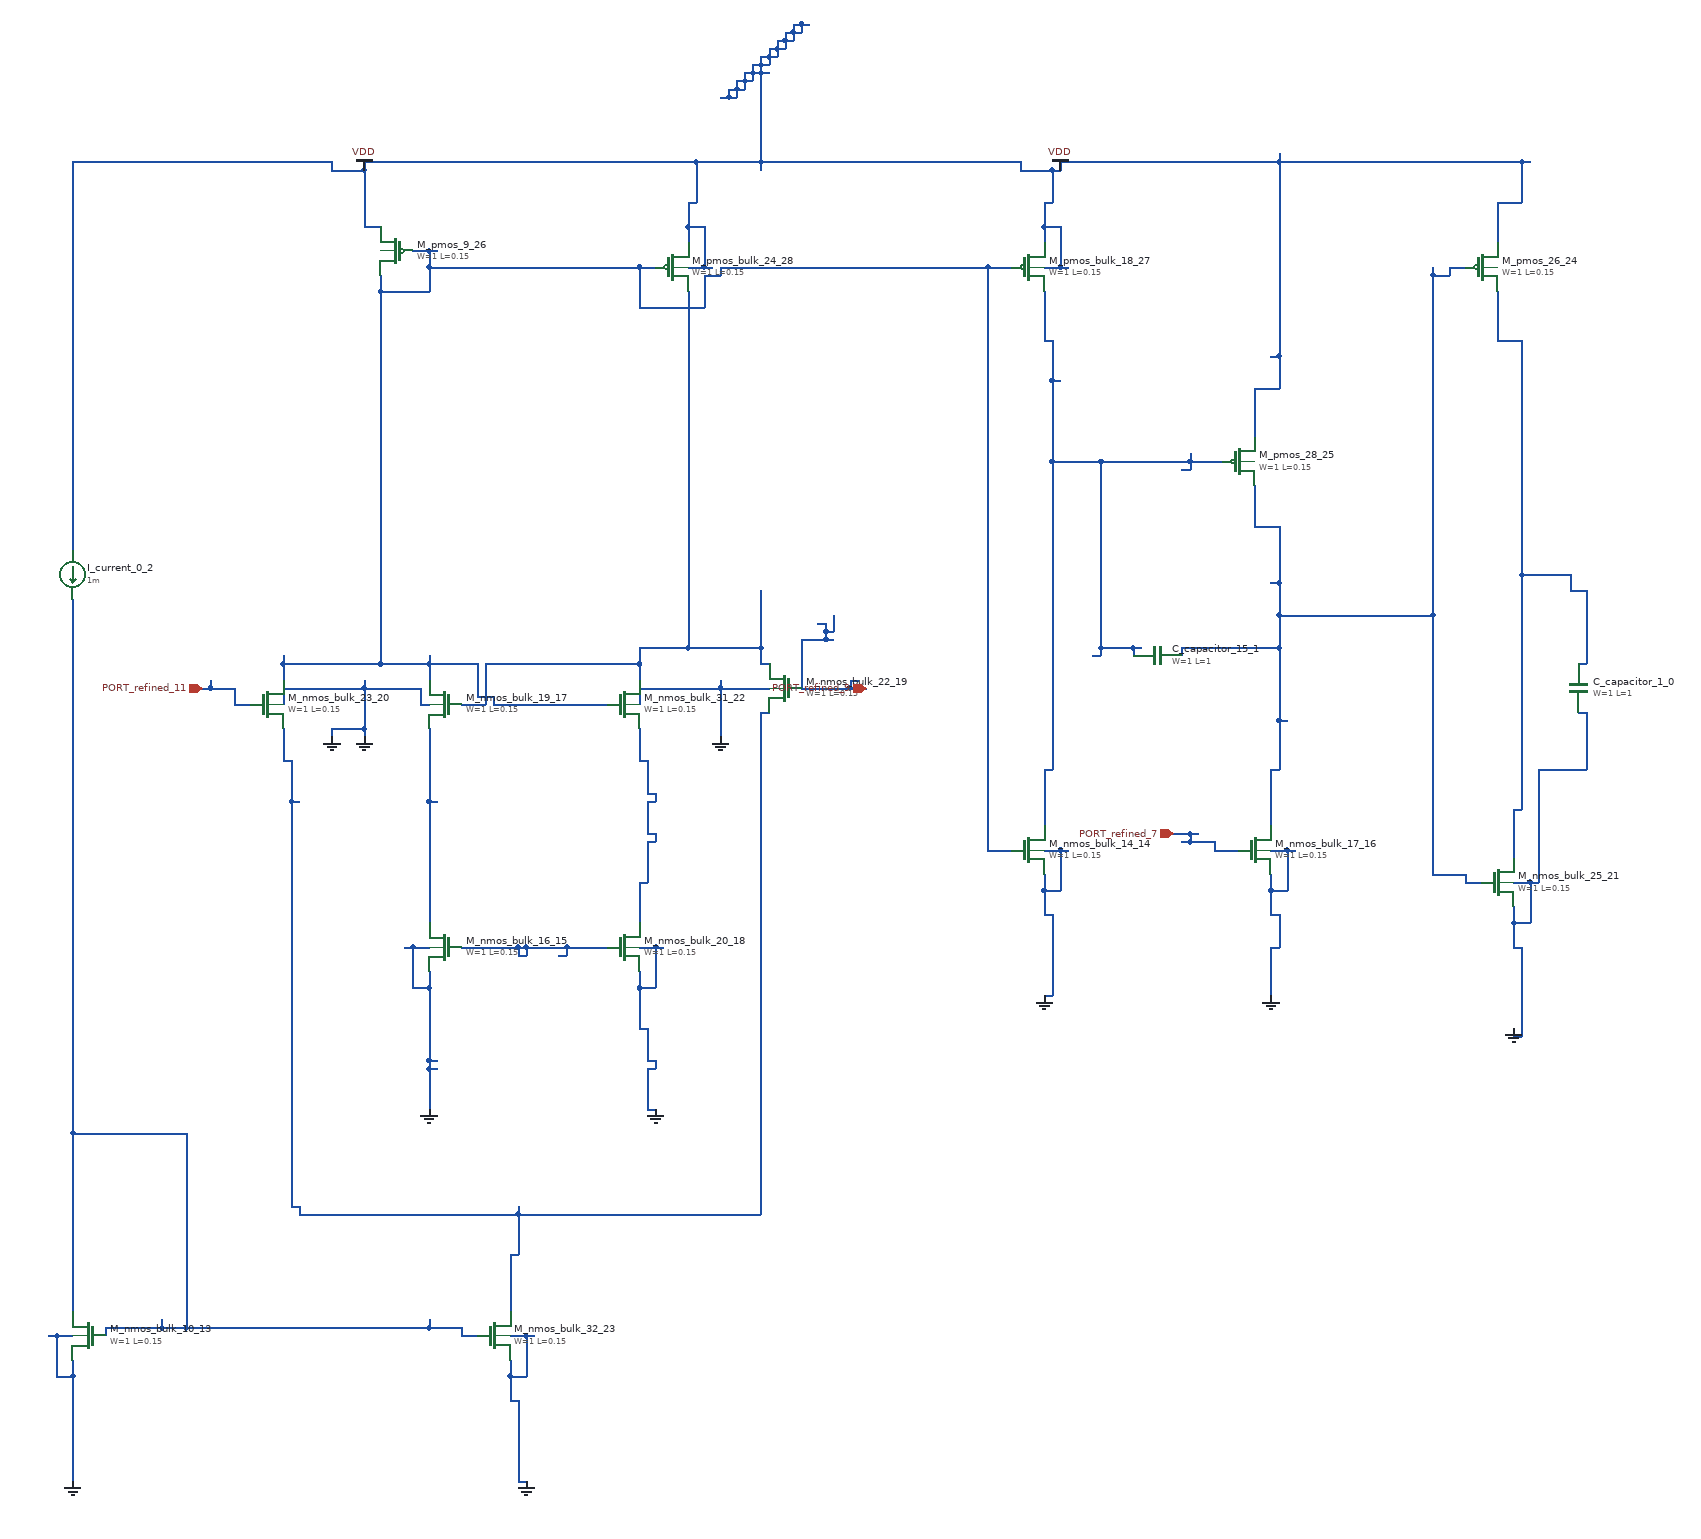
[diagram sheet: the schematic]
v {xschem version=3.4.8 file_version=1.2}
G {}
K {}
V {}
S {}
E {}
C {sky130_fd_pr/cap_mim_m3_1.sym} 2020 880 0 0 {name="C_capacitor_1_0" model=cap_mim_m3_1 W=1 L=1 MF=1 spiceprefix=X}
C {sky130_fd_pr/cap_mim_m3_1.sym} 1500 840 1 0 {name="C_capacitor_15_1" model=cap_mim_m3_1 W=1 L=1 MF=1 spiceprefix=X}
C {devices/isource.sym} 160 740 0 0 {name="I_current_0_2" value=1m}
C {devices/gnd.sym} 720 1860 0 0 {name="l_gnd_2_3" lab="GND"}
C {devices/gnd.sym} 520 940 0 0 {name="l_gnd_21_4" lab="GND"}
C {devices/gnd.sym} 960 940 0 0 {name="l_gnd_27_5" lab="GND"}
C {devices/gnd.sym} 160 1860 0 0 {name="l_gnd_3_6" lab="GND"}
C {devices/gnd.sym} 480 940 0 0 {name="l_gnd_35_7" lab="GND"}
C {devices/gnd.sym} 1940 1300 0 0 {name="l_gnd_4_8" lab="GND"}
C {devices/gnd.sym} 1640 1260 0 0 {name="l_gnd_5_9" lab="GND"}
C {devices/gnd.sym} 1360 1260 0 0 {name="l_gnd_6_10" lab="GND"}
C {devices/gnd.sym} 880 1400 0 0 {name="l_gnd_7_11" lab="GND"}
C {devices/gnd.sym} 600 1400 0 0 {name="l_gnd_8_12" lab="GND"}
C {sky130_fd_pr/nfet_01v8.sym} 180 1680 0 1 {name="M_nmos_bulk_10_13"
W=1
L=0.15
nf=1 
mult=1
ad="expr('int((@nf + 1)/2) * @W / @nf * 0.29')"
pd="expr('2*int((@nf + 1)/2) * (@W / @nf + 0.29)')"
as="expr('int((@nf + 2)/2) * @W / @nf * 0.29')"
ps="expr('2*int((@nf + 2)/2) * (@W / @nf + 0.29)')"
nrd="expr('0.29 / @W ')" nrs="expr('0.29 / @W ')"
sa=0 sb=0 sd=0
model=nfet_01v8
spiceprefix=X
}
C {sky130_fd_pr/nfet_01v8.sym} 1340 1080 0 0 {name="M_nmos_bulk_14_14"
W=1
L=0.15
nf=1 
mult=1
ad="expr('int((@nf + 1)/2) * @W / @nf * 0.29')"
pd="expr('2*int((@nf + 1)/2) * (@W / @nf + 0.29)')"
as="expr('int((@nf + 2)/2) * @W / @nf * 0.29')"
ps="expr('2*int((@nf + 2)/2) * (@W / @nf + 0.29)')"
nrd="expr('0.29 / @W ')" nrs="expr('0.29 / @W ')"
sa=0 sb=0 sd=0
model=nfet_01v8
spiceprefix=X
}
C {sky130_fd_pr/nfet_01v8.sym} 620 1200 0 1 {name="M_nmos_bulk_16_15"
W=1
L=0.15
nf=1 
mult=1
ad="expr('int((@nf + 1)/2) * @W / @nf * 0.29')"
pd="expr('2*int((@nf + 1)/2) * (@W / @nf + 0.29)')"
as="expr('int((@nf + 2)/2) * @W / @nf * 0.29')"
ps="expr('2*int((@nf + 2)/2) * (@W / @nf + 0.29)')"
nrd="expr('0.29 / @W ')" nrs="expr('0.29 / @W ')"
sa=0 sb=0 sd=0
model=nfet_01v8
spiceprefix=X
}
C {sky130_fd_pr/nfet_01v8.sym} 1620 1080 0 0 {name="M_nmos_bulk_17_16"
W=1
L=0.15
nf=1 
mult=1
ad="expr('int((@nf + 1)/2) * @W / @nf * 0.29')"
pd="expr('2*int((@nf + 1)/2) * (@W / @nf + 0.29)')"
as="expr('int((@nf + 2)/2) * @W / @nf * 0.29')"
ps="expr('2*int((@nf + 2)/2) * (@W / @nf + 0.29)')"
nrd="expr('0.29 / @W ')" nrs="expr('0.29 / @W ')"
sa=0 sb=0 sd=0
model=nfet_01v8
spiceprefix=X
}
C {sky130_fd_pr/nfet_01v8.sym} 620 900 0 1 {name="M_nmos_bulk_19_17"
W=1
L=0.15
nf=1 
mult=1
ad="expr('int((@nf + 1)/2) * @W / @nf * 0.29')"
pd="expr('2*int((@nf + 1)/2) * (@W / @nf + 0.29)')"
as="expr('int((@nf + 2)/2) * @W / @nf * 0.29')"
ps="expr('2*int((@nf + 2)/2) * (@W / @nf + 0.29)')"
nrd="expr('0.29 / @W ')" nrs="expr('0.29 / @W ')"
sa=0 sb=0 sd=0
model=nfet_01v8
spiceprefix=X
}
C {sky130_fd_pr/nfet_01v8.sym} 840 1200 0 0 {name="M_nmos_bulk_20_18"
W=1
L=0.15
nf=1 
mult=1
ad="expr('int((@nf + 1)/2) * @W / @nf * 0.29')"
pd="expr('2*int((@nf + 1)/2) * (@W / @nf + 0.29)')"
as="expr('int((@nf + 2)/2) * @W / @nf * 0.29')"
ps="expr('2*int((@nf + 2)/2) * (@W / @nf + 0.29)')"
nrd="expr('0.29 / @W ')" nrs="expr('0.29 / @W ')"
sa=0 sb=0 sd=0
model=nfet_01v8
spiceprefix=X
}
C {sky130_fd_pr/nfet_01v8.sym} 1040 880 0 1 {name="M_nmos_bulk_22_19"
W=1
L=0.15
nf=1 
mult=1
ad="expr('int((@nf + 1)/2) * @W / @nf * 0.29')"
pd="expr('2*int((@nf + 1)/2) * (@W / @nf + 0.29)')"
as="expr('int((@nf + 2)/2) * @W / @nf * 0.29')"
ps="expr('2*int((@nf + 2)/2) * (@W / @nf + 0.29)')"
nrd="expr('0.29 / @W ')" nrs="expr('0.29 / @W ')"
sa=0 sb=0 sd=0
model=nfet_01v8
spiceprefix=X
}
C {sky130_fd_pr/nfet_01v8.sym} 400 900 0 0 {name="M_nmos_bulk_23_20"
W=1
L=0.15
nf=1 
mult=1
ad="expr('int((@nf + 1)/2) * @W / @nf * 0.29')"
pd="expr('2*int((@nf + 1)/2) * (@W / @nf + 0.29)')"
as="expr('int((@nf + 2)/2) * @W / @nf * 0.29')"
ps="expr('2*int((@nf + 2)/2) * (@W / @nf + 0.29)')"
nrd="expr('0.29 / @W ')" nrs="expr('0.29 / @W ')"
sa=0 sb=0 sd=0
model=nfet_01v8
spiceprefix=X
}
C {sky130_fd_pr/nfet_01v8.sym} 1920 1120 0 0 {name="M_nmos_bulk_25_21"
W=1
L=0.15
nf=1 
mult=1
ad="expr('int((@nf + 1)/2) * @W / @nf * 0.29')"
pd="expr('2*int((@nf + 1)/2) * (@W / @nf + 0.29)')"
as="expr('int((@nf + 2)/2) * @W / @nf * 0.29')"
ps="expr('2*int((@nf + 2)/2) * (@W / @nf + 0.29)')"
nrd="expr('0.29 / @W ')" nrs="expr('0.29 / @W ')"
sa=0 sb=0 sd=0
model=nfet_01v8
spiceprefix=X
}
C {sky130_fd_pr/nfet_01v8.sym} 840 900 0 0 {name="M_nmos_bulk_31_22"
W=1
L=0.15
nf=1 
mult=1
ad="expr('int((@nf + 1)/2) * @W / @nf * 0.29')"
pd="expr('2*int((@nf + 1)/2) * (@W / @nf + 0.29)')"
as="expr('int((@nf + 2)/2) * @W / @nf * 0.29')"
ps="expr('2*int((@nf + 2)/2) * (@W / @nf + 0.29)')"
nrd="expr('0.29 / @W ')" nrs="expr('0.29 / @W ')"
sa=0 sb=0 sd=0
model=nfet_01v8
spiceprefix=X
}
C {sky130_fd_pr/nfet_01v8.sym} 680 1680 0 0 {name="M_nmos_bulk_32_23"
W=1
L=0.15
nf=1 
mult=1
ad="expr('int((@nf + 1)/2) * @W / @nf * 0.29')"
pd="expr('2*int((@nf + 1)/2) * (@W / @nf + 0.29)')"
as="expr('int((@nf + 2)/2) * @W / @nf * 0.29')"
ps="expr('2*int((@nf + 2)/2) * (@W / @nf + 0.29)')"
nrd="expr('0.29 / @W ')" nrs="expr('0.29 / @W ')"
sa=0 sb=0 sd=0
model=nfet_01v8
spiceprefix=X
}
C {sky130_fd_pr/pfet3_01v8.sym} 1900 360 0 0 {name="M_pmos_26_24"
W=1
L=0.15
body=VDD
nf=1
mult=1
ad="expr('int((@nf + 1)/2) * @W / @nf * 0.29')"
pd="expr('2*int((@nf + 1)/2) * (@W / @nf + 0.29)')"
as="expr('int((@nf + 2)/2) * @W / @nf * 0.29')"
ps="expr('2*int((@nf + 2)/2) * (@W / @nf + 0.29)')"
nrd="expr('0.29 / @W ')" nrs="expr('0.29 / @W ')"
sa=0 sb=0 sd=0
model=pfet_01v8
spiceprefix=X
}
C {sky130_fd_pr/pfet3_01v8.sym} 1600 600 0 0 {name="M_pmos_28_25"
W=1
L=0.15
body=VDD
nf=1
mult=1
ad="expr('int((@nf + 1)/2) * @W / @nf * 0.29')"
pd="expr('2*int((@nf + 1)/2) * (@W / @nf + 0.29)')"
as="expr('int((@nf + 2)/2) * @W / @nf * 0.29')"
ps="expr('2*int((@nf + 2)/2) * (@W / @nf + 0.29)')"
nrd="expr('0.29 / @W ')" nrs="expr('0.29 / @W ')"
sa=0 sb=0 sd=0
model=pfet_01v8
spiceprefix=X
}
C {sky130_fd_pr/pfet3_01v8.sym} 560 340 0 1 {name="M_pmos_9_26"
W=1
L=0.15
body=VDD
nf=1
mult=1
ad="expr('int((@nf + 1)/2) * @W / @nf * 0.29')"
pd="expr('2*int((@nf + 1)/2) * (@W / @nf + 0.29)')"
as="expr('int((@nf + 2)/2) * @W / @nf * 0.29')"
ps="expr('2*int((@nf + 2)/2) * (@W / @nf + 0.29)')"
nrd="expr('0.29 / @W ')" nrs="expr('0.29 / @W ')"
sa=0 sb=0 sd=0
model=pfet_01v8
spiceprefix=X
}
C {sky130_fd_pr/pfet_01v8.sym} 1340 360 0 0 {name="M_pmos_bulk_18_27"
W=1
L=0.15
nf=1
mult=1
ad="expr('int((@nf + 1)/2) * @W / @nf * 0.29')"
pd="expr('2*int((@nf + 1)/2) * (@W / @nf + 0.29)')"
as="expr('int((@nf + 2)/2) * @W / @nf * 0.29')"
ps="expr('2*int((@nf + 2)/2) * (@W / @nf + 0.29)')"
nrd="expr('0.29 / @W ')" nrs="expr('0.29 / @W ')"
sa=0 sb=0 sd=0
model=pfet_01v8
spiceprefix=X
}
C {sky130_fd_pr/pfet_01v8.sym} 900 360 0 0 {name="M_pmos_bulk_24_28"
W=1
L=0.15
nf=1
mult=1
ad="expr('int((@nf + 1)/2) * @W / @nf * 0.29')"
pd="expr('2*int((@nf + 1)/2) * (@W / @nf + 0.29)')"
as="expr('int((@nf + 2)/2) * @W / @nf * 0.29')"
ps="expr('2*int((@nf + 2)/2) * (@W / @nf + 0.29)')"
nrd="expr('0.29 / @W ')" nrs="expr('0.29 / @W ')"
sa=0 sb=0 sd=0
model=pfet_01v8
spiceprefix=X
}
C {devices/ipin.sym} 1140 880 0 0 {name="p_port_11_29" lab="PORT_refined_9"}
C {devices/ipin.sym} 1520 1060 0 0 {name="p_port_12_30" lab="PORT_refined_7"}
C {devices/ipin.sym} 320 880 0 0 {name="p_port_13_31" lab="PORT_refined_11"}
C {devices/vdd.sym} 520 240 0 0 {name="l_vdd_34_32" lab="VDD"}
C {devices/vdd.sym} 1380 240 0 0 {name="l_vdd_36_33" lab="VDD"}
N 710 1860 720 1860 {}
N 700 1760 710 1760 {}
N 140 1730 160 1730 {}
N 700 1730 720 1730 {}
N 130 1680 140 1680 {}
N 140 1680 160 1680 {}
N 700 1680 720 1680 {}
N 720 1680 730 1680 {}
N 870 1400 880 1400 {}
N 600 1350 610 1350 {}
N 870 1350 880 1350 {}
N 600 1340 610 1340 {}
N 870 1340 880 1340 {}
N 1940 1310 1950 1310 {}
N 860 1300 870 1300 {}
N 1360 1260 1370 1260 {}
N 580 1250 600 1250 {}
N 860 1250 880 1250 {}
N 570 1200 580 1200 {}
N 580 1200 600 1200 {}
N 860 1200 880 1200 {}
N 880 1200 890 1200 {}
N 1640 1200 1650 1200 {}
N 1940 1200 1950 1200 {}
N 1940 1170 1960 1170 {}
N 1360 1160 1370 1160 {}
N 1640 1160 1650 1160 {}
N 1360 1130 1380 1130 {}
N 1640 1130 1660 1130 {}
N 1940 1120 1960 1120 {}
N 1960 1120 1970 1120 {}
N 1360 1080 1380 1080 {}
N 1380 1080 1390 1080 {}
N 1640 1080 1660 1080 {}
N 1660 1080 1670 1080 {}
N 1970 980 2030 980 {}
N 480 930 520 930 {}
N 2020 910 2030 910 {}
N 590 900 600 900 {}
N 420 880 520 880 {}
N 520 880 590 880 {}
N 860 880 960 880 {}
N 960 880 1020 880 {}
N 140 1730 140 1680 {}
N 160 1860 160 1730 {}
N 160 1730 160 1710 {}
N 420 900 420 880 {}
N 480 940 480 930 {}
N 520 940 520 930 {}
N 520 930 520 880 {}
N 520 880 520 870 {}
N 580 1250 580 1200 {}
N 590 900 590 880 {}
N 600 1400 600 1350 {}
N 600 1350 600 1340 {}
N 600 1340 600 1250 {}
N 600 1250 600 1230 {}
N 700 1760 700 1730 {}
N 700 1730 700 1710 {}
N 710 1860 710 1760 {}
N 720 1730 720 1680 {}
N 860 1300 860 1250 {}
N 860 1250 860 1230 {}
N 860 900 860 880 {}
N 870 1400 870 1350 {}
N 870 1340 870 1300 {}
N 880 1350 880 1340 {}
N 880 1250 880 1200 {}
N 960 940 960 880 {}
N 960 880 960 870 {}
N 1360 1160 1360 1130 {}
N 1360 1130 1360 1110 {}
N 1370 1260 1370 1160 {}
N 1380 1130 1380 1080 {}
N 1640 1260 1640 1200 {}
N 1640 1160 1640 1130 {}
N 1640 1130 1640 1110 {}
N 1650 1200 1650 1160 {}
N 1660 1130 1660 1080 {}
N 1940 1310 1940 1300 {}
N 1940 1200 1940 1170 {}
N 1940 1170 1940 1150 {}
N 1950 1310 1950 1200 {}
N 1960 1170 1960 1120 {}
N 1970 1120 1970 980 {}
N 2030 980 2030 910 {}
N 640 1680 660 1680 {}
N 200 1670 270 1670 {}
N 270 1670 300 1670 {}
N 300 1670 600 1670 {}
N 600 1670 640 1670 {}
N 160 1430 300 1430 {}
N 160 1650 160 1430 {}
N 160 1430 160 770 {}
N 200 1680 200 1670 {}
N 270 1670 270 1660 {}
N 300 1670 300 1430 {}
N 600 1670 600 1660 {}
N 640 1680 640 1670 {}
N 700 1580 710 1580 {}
N 440 1530 710 1530 {}
N 710 1530 1010 1530 {}
N 430 1520 440 1520 {}
N 430 1020 440 1020 {}
N 420 970 430 970 {}
N 1010 910 1020 910 {}
N 420 970 420 930 {}
N 430 1520 430 1020 {}
N 430 1020 430 970 {}
N 440 1530 440 1520 {}
N 700 1650 700 1580 {}
N 710 1580 710 1530 {}
N 710 1530 710 1520 {}
N 1010 1530 1010 910 {}
N 360 900 380 900 {}
N 310 880 320 880 {}
N 320 880 330 880 {}
N 330 880 360 880 {}
N 330 880 330 870 {}
N 360 900 360 880 {}
N 1940 1030 1950 1030 {}
N 2020 850 2030 850 {}
N 2010 760 2030 760 {}
N 1950 740 2010 740 {}
N 1920 450 1950 450 {}
N 1920 450 1920 390 {}
N 1940 1090 1940 1030 {}
N 1950 1030 1950 740 {}
N 1950 740 1950 450 {}
N 2010 760 2010 740 {}
N 2030 850 2030 760 {}
N 1620 510 1650 510 {}
N 1640 470 1650 470 {}
N 920 360 940 360 {}
N 940 360 950 360 {}
N 1360 360 1380 360 {}
N 1380 360 1390 360 {}
N 520 310 540 310 {}
N 920 310 940 310 {}
N 1360 310 1380 310 {}
N 920 280 930 280 {}
N 1360 280 1370 280 {}
N 1920 280 1950 280 {}
N 480 240 520 240 {}
N 1330 240 1370 240 {}
N 1370 240 1380 240 {}
N 160 230 480 230 {}
N 520 230 930 230 {}
N 930 230 1010 230 {}
N 1010 230 1330 230 {}
N 1380 230 1650 230 {}
N 1650 230 1950 230 {}
N 1950 230 1960 230 {}
N 960 150 970 150 {}
N 970 150 980 150 {}
N 970 140 980 140 {}
N 980 140 990 140 {}
N 980 130 990 130 {}
N 990 130 1000 130 {}
N 990 120 1000 120 {}
N 1000 120 1010 120 {}
N 1010 120 1020 120 {}
N 1000 110 1010 110 {}
N 1010 110 1020 110 {}
N 1010 100 1020 100 {}
N 1020 100 1030 100 {}
N 1020 90 1030 90 {}
N 1030 90 1040 90 {}
N 1030 80 1040 80 {}
N 1040 80 1050 80 {}
N 1040 70 1050 70 {}
N 1050 70 1060 70 {}
N 1050 60 1060 60 {}
N 1060 60 1070 60 {}
N 160 710 160 230 {}
N 480 240 480 230 {}
N 520 310 520 240 {}
N 520 240 520 230 {}
N 920 330 920 310 {}
N 920 310 920 280 {}
N 930 280 930 230 {}
N 940 360 940 310 {}
N 970 150 970 140 {}
N 980 150 980 140 {}
N 980 140 980 130 {}
N 990 140 990 130 {}
N 990 130 990 120 {}
N 1000 130 1000 120 {}
N 1000 120 1000 110 {}
N 1010 240 1010 230 {}
N 1010 230 1010 120 {}
N 1010 120 1010 110 {}
N 1010 110 1010 100 {}
N 1020 110 1020 100 {}
N 1020 100 1020 90 {}
N 1030 100 1030 90 {}
N 1030 90 1030 80 {}
N 1040 90 1040 80 {}
N 1040 80 1040 70 {}
N 1050 80 1050 70 {}
N 1050 70 1050 60 {}
N 1060 70 1060 60 {}
N 1330 240 1330 230 {}
N 1360 330 1360 310 {}
N 1360 310 1360 280 {}
N 1370 280 1370 240 {}
N 1380 360 1380 310 {}
N 1380 240 1380 230 {}
N 1620 570 1620 510 {}
N 1650 510 1650 470 {}
N 1650 470 1650 230 {}
N 1650 230 1650 220 {}
N 1920 330 1920 280 {}
N 1950 280 1950 230 {}
N 640 900 670 900 {}
N 670 850 860 850 {}
N 1010 850 1020 850 {}
N 860 830 920 830 {}
N 920 830 1010 830 {}
N 670 900 670 850 {}
N 860 870 860 850 {}
N 860 850 860 830 {}
N 920 830 920 390 {}
N 1010 850 1010 830 {}
N 1010 830 1010 760 {}
N 1360 980 1370 980 {}
N 1420 840 1430 840 {}
N 1430 830 1470 830 {}
N 1470 830 1480 830 {}
N 1530 610 1540 610 {}
N 1370 600 1430 600 {}
N 1430 600 1540 600 {}
N 1540 600 1580 600 {}
N 1370 500 1380 500 {}
N 1360 450 1370 450 {}
N 1360 1050 1360 980 {}
N 1360 450 1360 390 {}
N 1370 980 1370 600 {}
N 1370 600 1370 500 {}
N 1370 500 1370 450 {}
N 1430 840 1430 830 {}
N 1430 830 1430 600 {}
N 1470 840 1470 830 {}
N 1540 610 1540 600 {}
N 1540 600 1540 590 {}
N 1290 1080 1320 1080 {}
N 680 900 820 900 {}
N 660 890 680 890 {}
N 420 850 540 850 {}
N 540 850 600 850 {}
N 600 850 660 850 {}
N 860 410 940 410 {}
N 540 390 600 390 {}
N 940 370 960 370 {}
N 600 360 860 360 {}
N 860 360 880 360 {}
N 960 360 1290 360 {}
N 1290 360 1320 360 {}
N 580 340 600 340 {}
N 600 340 610 340 {}
N 420 870 420 850 {}
N 420 850 420 840 {}
N 540 850 540 390 {}
N 540 390 540 370 {}
N 600 870 600 850 {}
N 600 850 600 840 {}
N 600 390 600 360 {}
N 600 360 600 340 {}
N 660 890 660 850 {}
N 680 900 680 890 {}
N 860 410 860 360 {}
N 940 410 940 370 {}
N 960 370 960 360 {}
N 1290 1080 1290 360 {}
N 600 1020 610 1020 {}
N 600 1170 600 1020 {}
N 600 1020 600 930 {}
N 710 1210 720 1210 {}
N 760 1210 770 1210 {}
N 640 1200 710 1200 {}
N 710 1200 720 1200 {}
N 720 1200 770 1200 {}
N 770 1200 820 1200 {}
N 710 1210 710 1200 {}
N 720 1210 720 1200 {}
N 770 1210 770 1200 {}
N 1880 1120 1900 1120 {}
N 1840 1110 1880 1110 {}
N 1640 980 1650 980 {}
N 1650 920 1660 920 {}
N 1530 830 1650 830 {}
N 1650 790 1840 790 {}
N 1640 750 1650 750 {}
N 1620 680 1650 680 {}
N 1840 370 1860 370 {}
N 1860 360 1880 360 {}
N 1530 840 1530 830 {}
N 1620 680 1620 630 {}
N 1640 1050 1640 980 {}
N 1650 980 1650 920 {}
N 1650 920 1650 830 {}
N 1650 830 1650 790 {}
N 1650 790 1650 750 {}
N 1650 750 1650 680 {}
N 1840 1110 1840 790 {}
N 1840 790 1840 370 {}
N 1840 370 1840 360 {}
N 1860 370 1860 360 {}
N 1880 1120 1880 1110 {}
N 1570 1080 1600 1080 {}
N 1530 1070 1540 1070 {}
N 1540 1070 1570 1070 {}
N 1520 1060 1540 1060 {}
N 1540 1060 1550 1060 {}
N 1540 1070 1540 1060 {}
N 1570 1080 1570 1070 {}
N 860 1120 870 1120 {}
N 870 1070 880 1070 {}
N 870 1060 880 1060 {}
N 870 1020 880 1020 {}
N 870 1010 880 1010 {}
N 860 970 870 970 {}
N 860 1170 860 1120 {}
N 860 970 860 930 {}
N 870 1120 870 1070 {}
N 870 1060 870 1020 {}
N 870 1010 870 970 {}
N 880 1070 880 1060 {}
N 880 1020 880 1010 {}
N 1060 880 1120 880 {}
N 1120 880 1140 880 {}
N 1120 870 1130 870 {}
N 1060 820 1090 820 {}
N 1090 820 1100 820 {}
N 1090 810 1100 810 {}
N 1080 800 1090 800 {}
N 1060 880 1060 820 {}
N 1090 820 1090 810 {}
N 1090 810 1090 800 {}
N 1100 810 1100 790 {}
N 1120 880 1120 870 {}
